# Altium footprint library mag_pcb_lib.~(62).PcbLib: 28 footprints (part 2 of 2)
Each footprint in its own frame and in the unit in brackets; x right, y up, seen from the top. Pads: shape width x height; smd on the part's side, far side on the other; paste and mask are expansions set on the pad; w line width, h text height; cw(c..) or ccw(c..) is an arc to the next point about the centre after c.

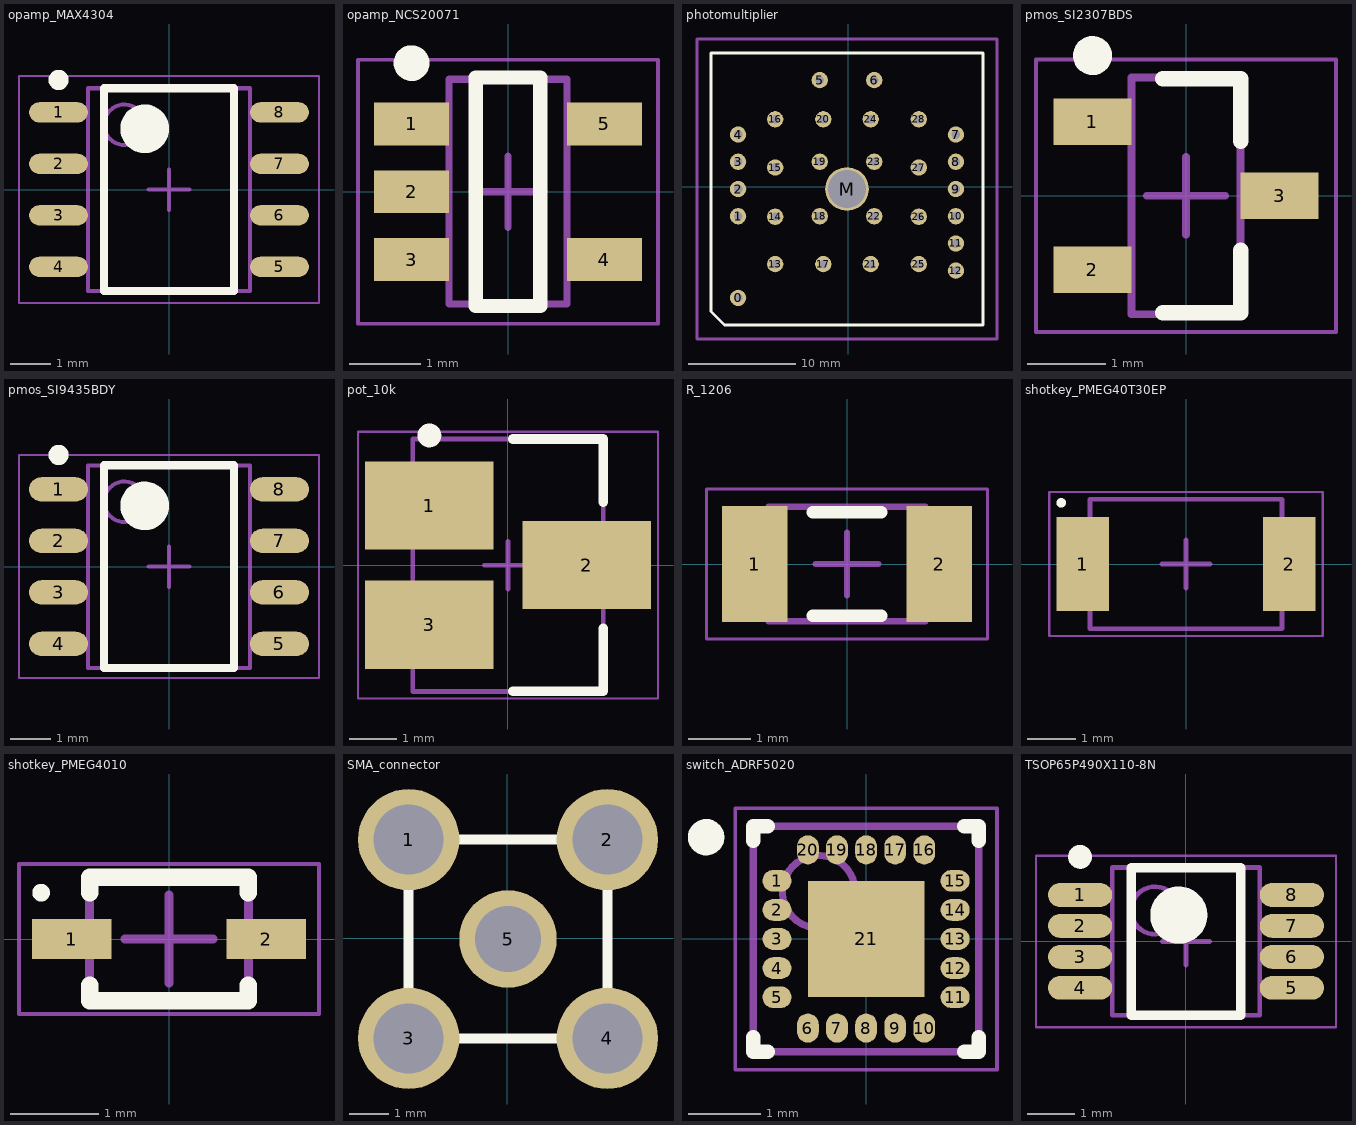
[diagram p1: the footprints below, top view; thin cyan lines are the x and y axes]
## opamp_MAX4304 [mm] "SOIC, 8-Leads, Body 4.90x3.90mm, Pitch 1.27mm, IPC Medium Density"
height 1.76
pads (8):
  oval 1.45x0.5 smd: 1(-2.725,1.905) 2(-2.725,0.635) 3(-2.725,-0.635) 4(-2.725,-1.905) 5(2.725,-1.905) 6(2.725,-0.635) 7(2.725,0.635) 8(2.725,1.905)
Top Overlay:
  circle w0.6: c-0.6,1.5 r0.3
  circle w0.25: c-2.725,2.705 r0.125
  lines w0.2: -1.6,-2.5 1.6,-2.5 1.6,2.5 -1.6,2.5 -1.6,-2.5
Mechanical 13:
  circle w0.1: c-1.1,1.6 r0.5
  lines w0.1: -2,-2.5 2,-2.5 2,2.5 -2,2.5 -2,-2.5
Mechanical 15:
  lines w0.05: -3.7,-2.8 3.7,-2.8 3.7,2.8 -3.7,2.8 -3.7,-2.8
  lines w0.1: -0.5,0 0.5,0 ; 0,-0.5 0,0.5
3D body: height 1.76, standoff 0.25, extent -2,-2.5 2,2.5

## opamp_NCS20071 [mm]
height 1.1
pads (5):
  rect 1.05x0.6 smd: 1(-1.35,0.95) 2(-1.35,0) 3(-1.35,-0.95) 4(1.35,-0.95) 5(1.35,0.95)
Top Overlay:
  circle w0.25: c-1.35,1.8 r0.125
  lines w0.2: -0.45,-1.6 -0.45,1.6 0.45,1.6 0.45,-1.6 -0.45,-1.6
Mechanical 13:
  lines w0.1: -0.825,-1.575 0.825,-1.575 0.825,1.575 -0.825,1.575 -0.825,-1.575
Mechanical 15:
  lines w0.05: -2.1,-1.85 2.1,-1.85 2.1,1.85 -2.1,1.85 -2.1,-1.85
  lines w0.1: -0.5,0 0.5,0 ; 0,-0.5 0,0.5
3D body: height 1.1, standoff 0.05, extent -0.825,-1.575 0.825,1.575

## photomultiplier [mil]
pads (30):
  round 60 hole 32: 0(-403.69,-407.85) 1(-403.69,-107.85) 2(-403.69,-7.85) 3(-403.69,92.15) 4(-403.69,192.15) 5(-103.69,392.15) 6(96.31,392.15) 7(396.31,192.15) 8(396.31,92.15) 9(396.31,-7.85) 10(396.31,-107.85) 11(396.31,-207.85) 12(396.31,-307.85) 13(-267.69,-283.85) 14(-267.69,-109.85) 15(-267.69,71.15) 16(-267.69,248.15) 17(-90.69,-283.85) 18(-103.69,-107.85) 19(-103.69,92.15) 20(-90.69,248.15) 21(83.31,-283.85) 22(96.31,-107.85) 23(96.31,92.15) 24(83.31,248.15) 25(260.31,-283.85) 26(260.31,-109.85) 27(260.31,71.15) 28(260.31,248.15)
  round 160 hole 140: M(-3.69,-7.85)
Top Overlay:
  lines w10: -503.69,-457.85 -503.69,492.15 496.31,492.15 496.31,-507.85 -453.69,-507.85 -503.69,-457.85
Mechanical 4:
  lines w10: -554.87,-559.03 547.5,-559.03 547.5,543.33 -554.87,543.33 -554.87,-559.03

## pmos_SI2307BDS [mm]
height 1.12
pads (3):
  rect 1x0.6 smd: 1(-1.2,0.95) 2(-1.2,-0.95) 3(1.2,0)
Top Overlay:
  circle w0.25: c-1.2,1.8 r0.125
  lines w0.2: -0.3,-1.5 0.7,-1.5 0.7,-0.7 ; -0.3,1.5 0.7,1.5 0.7,0.7
Mechanical 13:
  lines w0.1: -0.7,-1.52 0.7,-1.52 0.7,1.52 -0.7,1.52 -0.7,-1.52
Mechanical 15:
  lines w0.05: -1.925,-1.75 1.925,-1.75 1.925,1.75 -1.925,1.75 -1.925,-1.75
  lines w0.1: -0.5,0 0.5,0 ; 0,-0.5 0,0.5
3D body: height 1.12, standoff 0.1, extent -0.7,-1.52 0.7,1.52

## pmos_SI9435BDY [mm]
height 1.75
pads (8):
  oval 1.45x0.6 smd: 1(-2.725,1.905) 2(-2.725,0.635) 3(-2.725,-0.635) 4(-2.725,-1.905) 5(2.725,-1.905) 6(2.725,-0.635) 7(2.725,0.635) 8(2.725,1.905)
Top Overlay:
  circle w0.25: c-2.725,2.755 r0.125
  circle w0.6: c-0.6,1.5 r0.3
  lines w0.2: -1.6,-2.5 -1.6,2.5 1.6,2.5 1.6,-2.5 -1.6,-2.5
Mechanical 13:
  circle w0.1: c-1.1,1.6 r0.5
  lines w0.1: -2,-2.5 -2,2.5 2,2.5 2,-2.5 -2,-2.5
Mechanical 15:
  lines w0.05: -3.7,-2.75 -3.7,2.75 3.7,2.75 3.7,-2.75 -3.7,-2.75
  lines w0.1: -0.5,0 0.5,0 ; 0,-0.5 0,0.5
3D body: height 1.75, standoff 0.2, extent -2,-2.5 2,2.5

## pot_10k [mm]
height 5.8
pads (3):
  rect 2.7x1.85 smd: 1(-1.65,1.25) 2(1.65,0) 3(-1.65,-1.25)
Top Overlay:
  circle w0.25: c-1.65,2.725 r0.125
  lines w0.2: 0.1,-2.65 2,-2.65 2,-1.325 ; 0.1,2.65 2,2.65 2,1.325
Mechanical 13:
  lines w0.1: -2,-2.65 -2,2.65 2,2.65 2,-2.65 -2,-2.65
Mechanical 15:
  lines w0.05: -3.15,-2.8 -3.15,2.8 3.15,2.8 3.15,-2.8 -3.15,-2.8
  lines w0.1: -0.5,0 0.5,0 ; 0,-0.5 0,0.5
3D body: height 5.8, standoff 0, extent -2,-2.65 2,2.65

## R_1206 [mm]
height 0.8
pads (2):
  rect 1.05x1.85 smd: 1(-1.475,0) 2(1.475,0)
Top Overlay:
  lines w0.2: -0.55,-0.825 0.55,-0.825 ; -0.55,0.825 0.55,0.825
Mechanical 13:
  lines w0.1: -1.255,-0.915 1.255,-0.915 1.255,0.915 -1.255,0.915 -1.255,-0.915
Mechanical 15:
  lines w0.05: -2.25,-1.2 2.25,-1.2 2.25,1.2 -2.25,1.2 -2.25,-1.2
  lines w0.1: -0.5,0 0.5,0 ; 0,-0.5 0,0.5
3D body: height 0.8, standoff 0, extent 0.775,-0.915 1.255,0.915
3D body: height 0.8, standoff 0, extent -1.255,-0.915 -0.775,0.915
3D body: height 0.8, standoff 0, extent -0.775,-0.915 0.775,0.915

## shotkey_PMEG40T30EP [mm]
height 1.1
pads (2):
  rect 1.1x1.95 smd: 1(-2.15,0) 2(2.15,0)
Top Overlay:
  circle w0.1: c-2.6,1.275 r0.05
Mechanical 13:
  lines w0.1: -2,-1.35 -2,1.35 2,1.35 2,-1.35 -2,-1.35
Mechanical 15:
  lines w0.05: -2.85,-1.5 -2.85,1.5 2.85,1.5 2.85,-1.5 -2.85,-1.5
  lines w0.1: -0.5,0 0.5,0 ; 0,-0.5 0,0.5
3D body: height 1.1, standoff 0, extent -2,-1.35 2,1.35

## shotkey_PMEG4010 [mm]
height 0.8
pads (2):
  rect 0.9x0.45 smd: 1(-1.1,0) 2(1.1,0)
Top Overlay:
  circle w0.1: c-1.45,0.525 r0.05
  lines w0.2: -0.9,-0.525 -0.9,-0.7 0.9,-0.7 0.9,-0.525 ; -0.9,0.525 -0.9,0.7 0.9,0.7 0.9,0.525
Mechanical 13:
  lines w0.1: -0.9,-0.675 -0.9,0.675 0.9,0.675 0.9,-0.675 -0.9,-0.675
Mechanical 15:
  lines w0.05: -1.7,-0.85 -1.7,0.85 1.7,0.85 1.7,-0.85 -1.7,-0.85
  lines w0.1: -0.5,0 0.5,0 ; 0,-0.5 0,0.5
3D body: height 0.8, standoff 0, extent -0.9,-0.675 0.9,0.675

## SMA_connector [mm]
pads (5):
  round 2.6 / inner round 1.8 / far side round 2.6 hole 1.8: 1(-2.525,2.525) 2(2.575,2.525) 3(-2.525,-2.575) 4(2.575,-2.575)
  round 2.5 / inner round 1.8 / far side round 2.5 hole 1.7: 5(0.025,-0.025)
Top Overlay:
  lines w0.254: -2.525,-2.575 2.575,-2.575 2.575,2.525 -2.525,2.525 -2.525,-2.575

## switch_ADRF5020 [mm] "PQFN, 20-Leads, Body 3.00x3.00mm, Pitch 0.40mm, Thermal Pad 1.60x1.60mm, IPC Medium Density"
height 0.78
pads (21):
  oval 0.4x0.3 smd: 1(-1.225,0.8) 2(-1.225,0.4) 3(-1.225,0) 4(-1.225,-0.4) 5(-1.225,-0.8) 11(1.225,-0.8) 12(1.225,-0.4) 13(1.225,0) 14(1.225,0.4) 15(1.225,0.8)
  oval 0.3x0.4 smd: 6(-0.8,-1.225) 7(-0.4,-1.225) 8(0,-1.225) 9(0.4,-1.225) 10(0.8,-1.225) 16(0.8,1.225) 17(0.4,1.225) 18(0,1.225) 19(-0.4,1.225) 20(-0.8,1.225)
  rect 1.6x1.6 smd: 21(0,0)
Top Overlay:
  circle w0.25: c-2.2,1.4 r0.125
  lines w0.2: -1.55,-1.35 -1.55,-1.55 -1.35,-1.55 ; -1.55,1.35 -1.55,1.55 -1.35,1.55 ; 1.35,-1.55 1.55,-1.55 1.55,-1.35 ; 1.35,1.55 1.55,1.55 1.55,1.35
Mechanical 13:
  circle w0.1: c-0.65,0.65 r0.5
  lines w0.1: -1.55,-1.55 1.55,-1.55 1.55,1.55 -1.55,1.55 -1.55,-1.55
Mechanical 15:
  lines w0.05: -1.8,-1.8 1.8,-1.8 1.8,1.8 -1.8,1.8 -1.8,-1.8
  lines w0.1: -0.5,0 0.5,0 ; 0,-0.5 0,0.5
3D body: height 0.78, standoff 0.16, extent -1.55,-1.55 1.55,1.55

## TSOP65P490X110-8N [mm] "TSOP, 8-Leads, Body 3.00x3.00mm, Pitch 0.65mm, IPC Medium Density"
height 1.1
pads (8):
  oval 1.35x0.5 smd: 1(-2.225,0.975) 2(-2.225,0.325) 3(-2.225,-0.325) 4(-2.225,-0.975) 5(2.225,-0.975) 6(2.225,-0.325) 7(2.225,0.325) 8(2.225,0.975)
Top Overlay:
  circle w0.6: c-0.15,0.55 r0.3
  circle w0.25: c-2.225,1.775 r0.125
  lines w0.2: -1.15,-1.55 1.15,-1.55 1.15,1.55 -1.15,1.55 -1.15,-1.55
Mechanical 13:
  circle w0.1: c-0.65,0.65 r0.5
  lines w0.1: -1.55,-1.55 1.55,-1.55 1.55,1.55 -1.55,1.55 -1.55,-1.55
Mechanical 15:
  lines w0.05: -3.15,-1.8 3.15,-1.8 3.15,1.8 -3.15,1.8 -3.15,-1.8
  lines w0.1: -0.5,0 0.5,0 ; 0,-0.5 0,0.5
3D body: height 1.1, standoff 0.25, extent -1.55,-1.55 1.55,1.55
